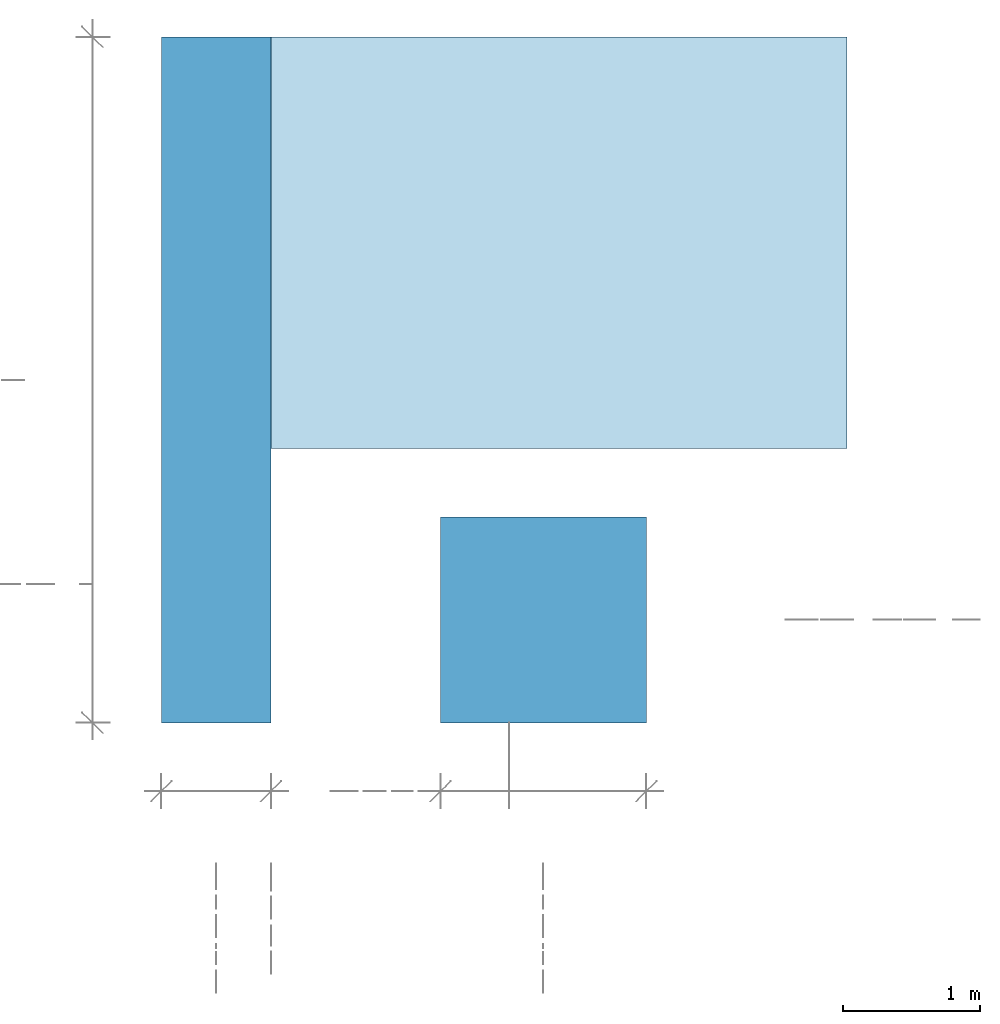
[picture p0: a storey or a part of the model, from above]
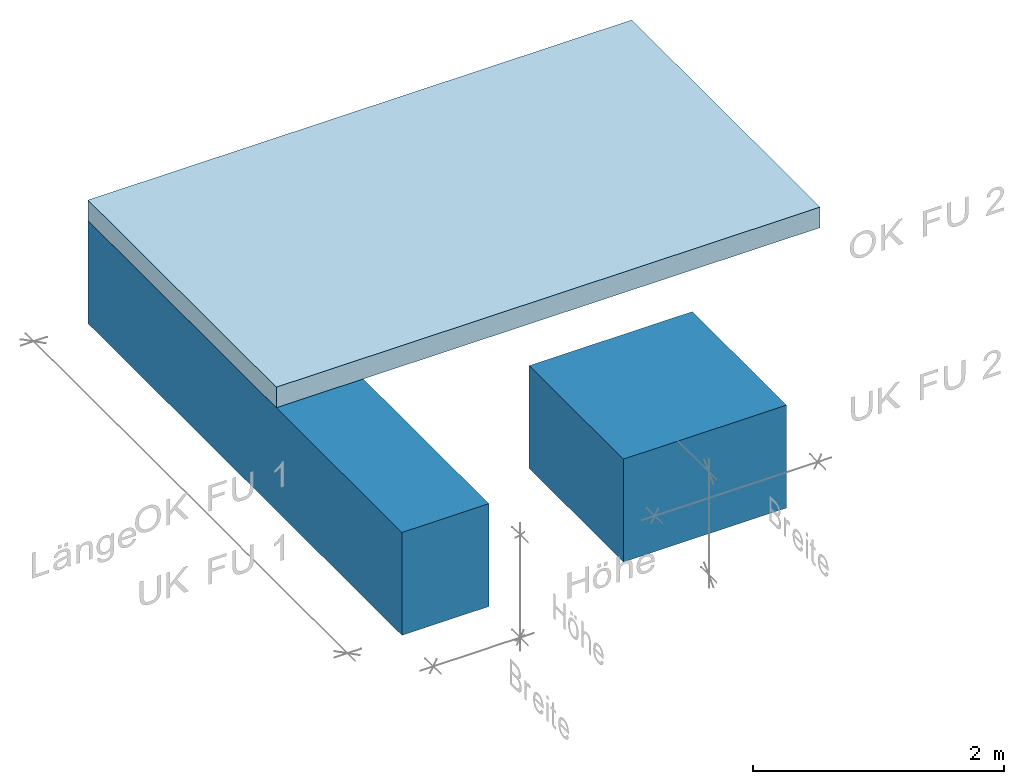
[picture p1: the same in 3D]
Properties of the parts of a building model (IFC4)

# File
Description: no view
File name: ÖBV_OEBV_Richtlinie_Fundamente.ifc
Time: 2024-03-13T09:35:00
Author: Oesterreichische Bautechnik Vereinigung
Organization: OEBV
Written by: ODA SDAI 24.5
Authorization: OEBV

# IfcSite, Liegenschaft
RefLatitude: 48, 8, 10, 320000; RefLongitude: 11, 41, 19, 320000

# IfcBuildingStorey, Geschoss 01
In: Gebäude
Elevation: 0 m

# IfcBuildingElementProxy (14)
In: Geschoss 01
Name | Allright_Bauteil_ID
macro | 0005Mak0000000017
macro | 0005Mak0000000028
macro | 0005Mak0000000039
macro | 0005Mak0000000157
macro | 0005Mak0000000191
macro | 0005Mak0000000084
macro | 0005Mak0000000096
 | 0005Mak0000000247
macro | 0005Mak0000003137
macro | 0005Mak0000003173
macro | 0005Mak0000000224
macro | 0005Mak0000003206
 | 0005Mak0000000144
 | 0005Mak0000000132

# IfcElementAssembly (14)
In: Geschoss 01
Name | Allright_Bauteil_ID
SpatialDim_Group | 0005Elg0000000018
SpatialDim_Group | 0005Elg0000000029
SpatialDim_Group | 0005Elg0000000040
SpatialDim_Group | 0005Elg0000000158
SpatialDim_Group | 0005Elg0000000192
SpatialDim_Group | 0005Elg0000000085
SpatialDim_Group | 0005Elg0000000097
SpatialDim_Group | 0005Elg0000000236
SpatialDim_Group | 0005Elg0000000169
SpatialDim_Group | 0005Elg0000000051
SpatialDim_Group | 0005Elg0000000225
SpatialDim_Group | 0005Elg0000000062
SpatialDim_Group | 0005Elg0000000121
SpatialDim_Group | 0005Elg0000000109

# IfcFooting (2)
In: Geschoss 01
Name | PredefinedType | Allright_Bauteil_ID
 | PAD_FOOTING | 0005EFu0000007462
 | STRIP_FOOTING | 0005SFu0000007475

# IfcSlab, PFU_02
In: Geschoss 01
Description: Plattenfundament; PredefinedType: BASESLAB; Material: C20/25
AllplanAttributes - Allright_Bauteil_ID: 0005ErE0000000002
